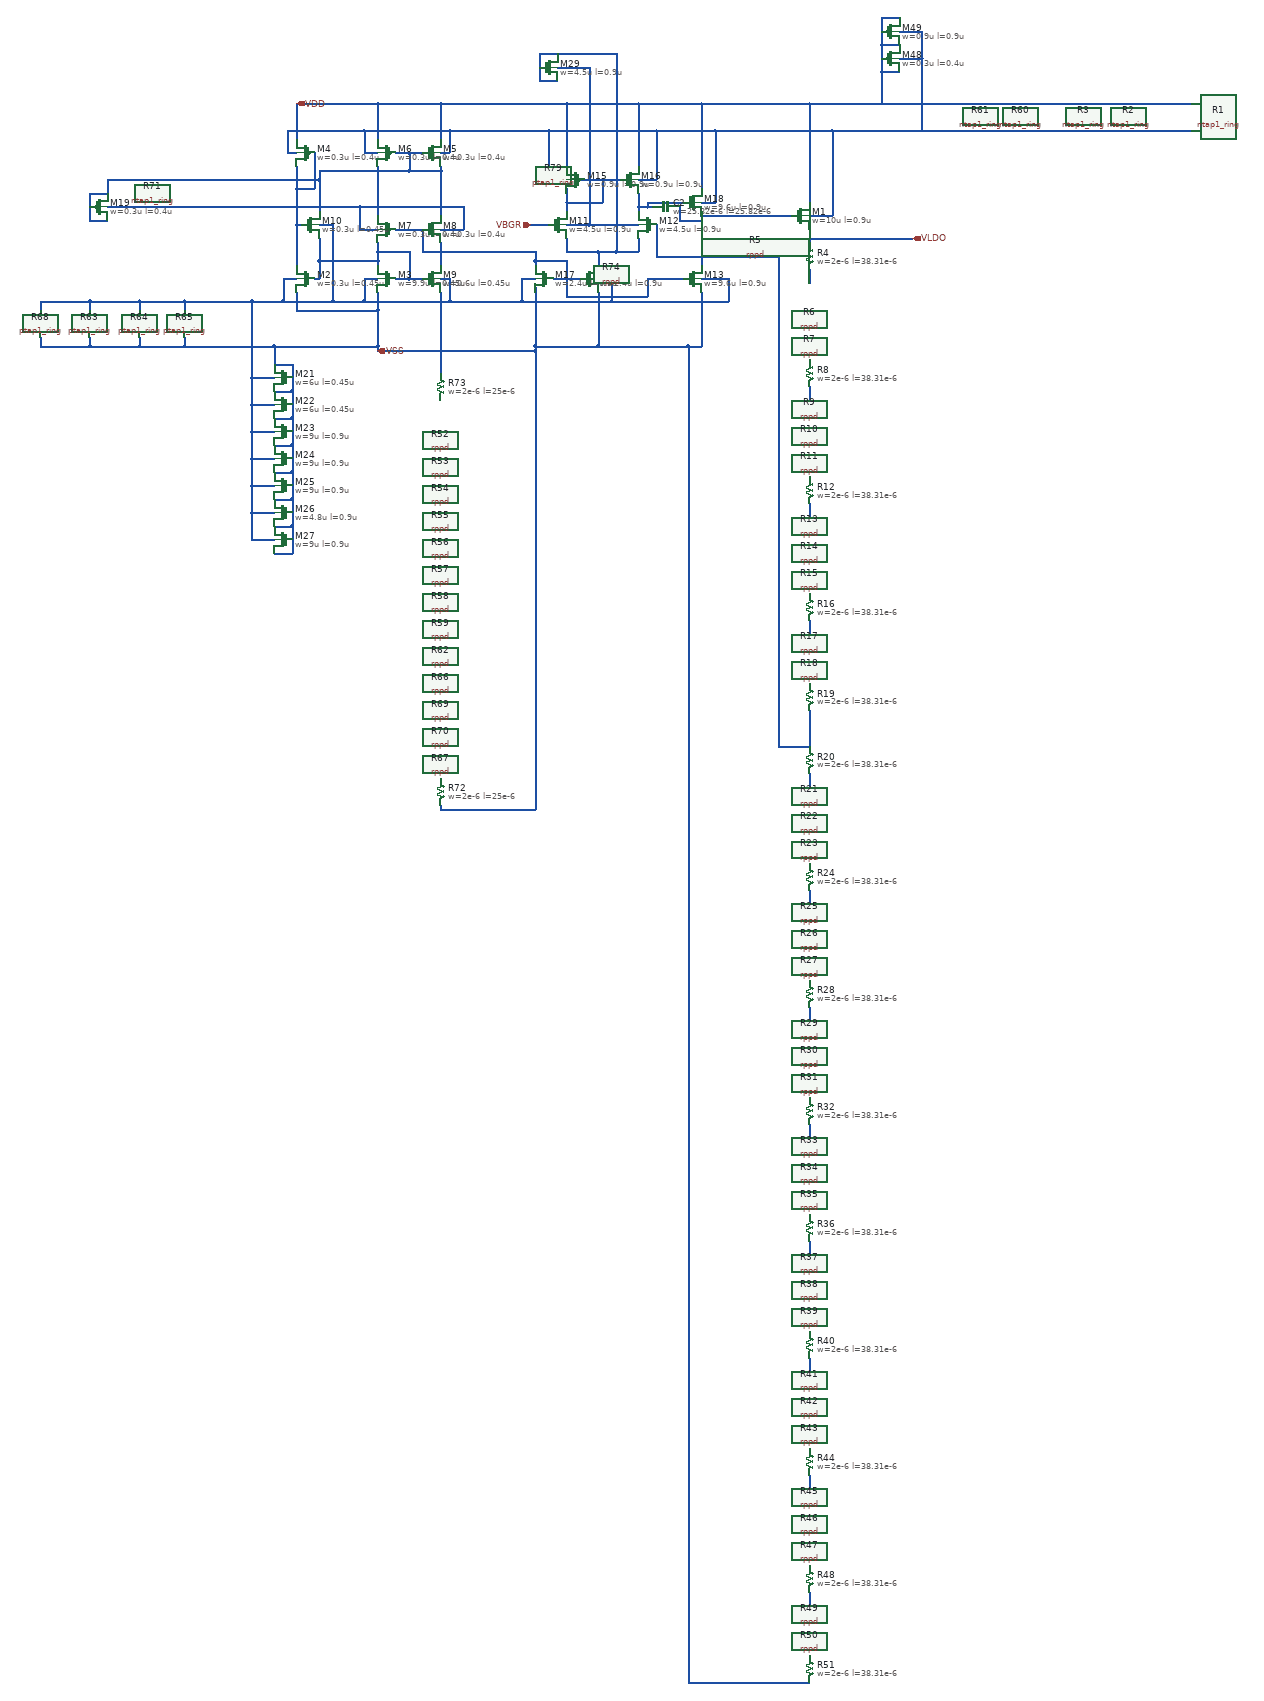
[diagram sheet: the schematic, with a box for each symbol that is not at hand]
v {xschem version=3.4.8RC file_version=1.3}
G {}
K {}
V {}
S {}
F {}
E {}
N -350 -1320 -240 -1320 {lab=VSS}
N -350 -1340 -350 -1320 {lab=VSS}
N -240 -1340 -240 -1320 {lab=VSS}
N -240 -1320 -130 -1320 {lab=VSS}
N -130 -1340 -130 -1320 {lab=VSS}
N -130 -1320 -30 -1320 {lab=VSS}
N -30 -1340 -30 -1320 {lab=VSS}
N 1520 -1860 2210 -1860 {lab=VDD}
N 210 -1160 210 -1100 {lab=VSS}
N 170 -1280 210 -1280 {lab=VSS}
N 170 -1220 210 -1220 {lab=VSS}
N 210 -1280 210 -1220 {lab=VSS}
N 170 -1320 170 -1280 {lab=VSS}
N 120 -1190 170 -1190 {lab=#net1}
N 120 -1250 120 -1190 {lab=#net1}
N 120 -1250 170 -1250 {lab=#net1}
N 170 -980 210 -980 {lab=VSS}
N 210 -1040 210 -980 {lab=VSS}
N 170 -1040 210 -1040 {lab=VSS}
N 210 -1100 210 -1040 {lab=VSS}
N 170 -920 210 -920 {lab=VSS}
N 210 -980 210 -920 {lab=VSS}
N 170 -1100 210 -1100 {lab=VSS}
N 170 -1160 210 -1160 {lab=VSS}
N 210 -1220 210 -1160 {lab=VSS}
N 120 -1130 170 -1130 {lab=#net1}
N 120 -1190 120 -1130 {lab=#net1}
N 120 -1070 170 -1070 {lab=#net1}
N 120 -1130 120 -1070 {lab=#net1}
N 120 -1010 170 -1010 {lab=#net1}
N 120 -1070 120 -1010 {lab=#net1}
N 120 -950 170 -950 {lab=#net1}
N 120 -1010 120 -950 {lab=#net1}
N 170 -860 210 -860 {lab=VSS}
N 210 -920 210 -860 {lab=VSS}
N 120 -890 170 -890 {lab=#net1}
N 120 -950 120 -890 {lab=#net1}
N 1360 -1610 1410 -1610 {lab=#net2}
N 470 -1750 500 -1750 {lab=#net3}
N 440 -1580 500 -1580 {lab=#net4}
N 400 -1510 400 -1500 {lab=#net5}
N 470 -1530 470 -1470 {lab=#net5}
N 400 -1530 470 -1530 {lab=#net5}
N 400 -1550 400 -1530 {lab=#net5}
N 400 -1440 400 -1400 {lab=VSS}
N 370 -1750 400 -1750 {lab=#net2}
N 400 -1720 400 -1610 {lab=#net6}
N 220 -1590 220 -1500 {lab=#net7}
N 270 -1510 270 -1470 {lab=#net5}
N 220 -1440 220 -1400 {lab=VSS}
N 270 -1590 300 -1590 {lab=#net1}
N 270 -1560 270 -1510 {lab=#net5}
N 220 -1590 230 -1590 {lab=#net7}
N 220 -1670 220 -1590 {lab=#net7}
N 260 -1750 260 -1670 {lab=#net7}
N 200 -1750 220 -1750 {lab=#net2}
N 540 -1750 560 -1750 {lab=#net2}
N 270 -1510 400 -1510 {lab=#net5}
N 400 -1530 400 -1510 {lab=#net5}
N 540 -1720 540 -1710 {lab=#net3}
N 540 -1530 540 -1500 {lab=#net4}
N 470 -1750 470 -1710 {lab=#net3}
N 440 -1750 470 -1750 {lab=#net3}
N 470 -1710 540 -1710 {lab=#net3}
N 270 -1690 270 -1620 {lab=#net3}
N 500 -1580 500 -1530 {lab=#net4}
N 500 -1530 540 -1530 {lab=#net4}
N 540 -1470 560 -1470 {lab=#net1}
N 470 -1470 500 -1470 {lab=#net5}
N 440 -1470 470 -1470 {lab=#net5}
N 220 -1670 260 -1670 {lab=#net7}
N 220 -1720 220 -1670 {lab=#net7}
N 260 -1470 270 -1470 {lab=#net5}
N 820 -1640 820 -1620 {lab=#net8}
N 820 -1560 820 -1530 {lab=#net9}
N 980 -1560 980 -1530 {lab=#net9}
N 750 -1510 750 -1500 {lab=#net4}
N 890 -1530 890 -1500 {lab=#net9}
N 820 -1470 860 -1470 {lab=#net4}
N 890 -1440 890 -1320 {lab=VSS}
N 750 -1450 750 -1320 {lab=VSS}
N 1000 -1470 1080 -1470 {lab=#net4}
N 1000 -1470 1000 -1430 {lab=#net4}
N 790 -1470 820 -1470 {lab=#net4}
N 820 -1430 1000 -1430 {lab=#net4}
N 820 -1470 820 -1430 {lab=#net4}
N 1120 -1470 1180 -1470 {lab=#net1}
N 980 -1630 980 -1620 {lab=#net10}
N 1120 -1640 1150 -1640 {lab=#net2}
N 780 -1690 820 -1690 {lab=#net2}
N 820 -1530 890 -1530 {lab=#net9}
N 890 -1470 920 -1470 {lab=#net1}
N 750 -1510 820 -1510 {lab=#net4}
N 820 -1510 820 -1470 {lab=#net4}
N 720 -1470 750 -1470 {lab=#net1}
N 900 -1690 940 -1690 {lab=#net8}
N 900 -1690 900 -1640 {lab=#net8}
N 850 -1690 900 -1690 {lab=#net8}
N 820 -1640 900 -1640 {lab=#net8}
N 820 -1670 820 -1640 {lab=#net8}
N 980 -1690 1020 -1690 {lab=#net2}
N 1000 -1630 1010 -1630 {lab=#net10}
N 1000 -1640 1080 -1640 {lab=#net10}
N 1000 -1640 1000 -1630 {lab=#net10}
N 980 -1630 1000 -1630 {lab=#net10}
N 980 -1660 980 -1630 {lab=#net10}
N 1070 -1630 1070 -1600 {lab=#net11}
N 1070 -1600 1120 -1600 {lab=#net11}
N 1120 -1610 1120 -1600 {lab=#net11}
N 1090 -1320 1120 -1320 {lab=VSS}
N 540 -1710 540 -1610 {lab=#net3}
N 1120 -1440 1120 -1320 {lab=VSS}
N 540 -1530 750 -1530 {lab=#net4}
N 750 -1530 750 -1510 {lab=#net4}
N 1120 -1600 1120 -1500 {lab=#net11}
N 1120 -1610 1320 -1610 {lab=#net11}
N 1120 -1620 1120 -1610 {lab=#net11}
N 400 -1400 400 -1320 {lab=VSS}
N 220 -1400 400 -1400 {lab=VSS}
N 1360 -1490 1360 -1460 {lab=#net12}
N 1360 -1560 1360 -1540 {lab=VLDO}
N 1360 -1580 1360 -1560 {lab=VLDO}
N 1360 -1560 1590 -1560 {lab=VLDO}
N 750 -1320 890 -1320 {lab=VSS}
N 1360 -1230 1360 -1200 {lab=#net13}
N 1360 -970 1360 -940 {lab=#net14}
N 1360 -710 1360 -680 {lab=#net15}
N 1360 -370 1360 -340 {lab=#net16}
N 1360 -110 1360 -80 {lab=#net17}
N 1360 150 1360 180 {lab=#net18}
N 1360 410 1360 440 {lab=#net19}
N 1360 670 1360 700 {lab=#net20}
N 1360 930 1360 960 {lab=#net21}
N 1360 1190 1360 1220 {lab=#net22}
N 1360 1450 1360 1480 {lab=#net23}
N 1290 -1520 1290 -430 {lab=#net24}
N 1020 -1520 1290 -1520 {lab=#net24}
N 1020 -1590 1020 -1520 {lab=#net24}
N 1290 -430 1360 -430 {lab=#net24}
N 1090 1650 1360 1650 {lab=VSS}
N 750 -1310 750 -290 {lab=VSS}
N 540 -290 750 -290 {lab=VSS}
N 740 -1590 780 -1590 {lab=VBGR}
N 370 -1800 370 -1750 {lab=#net2}
N 1410 -1800 1610 -1800 {lab=#net2}
N 560 -1800 560 -1750 {lab=#net2}
N 370 -1800 560 -1800 {lab=#net2}
N 780 -1800 780 -1690 {lab=#net2}
N 560 -1800 780 -1800 {lab=#net2}
N 1020 -1800 1020 -1690 {lab=#net2}
N 780 -1800 1020 -1800 {lab=#net2}
N 1150 -1800 1150 -1640 {lab=#net2}
N 1410 -1800 1410 -1610 {lab=#net2}
N 1150 -1800 1410 -1800 {lab=#net2}
N 200 -1800 370 -1800 {lab=#net2}
N 200 -1800 200 -1750 {lab=#net2}
N 540 -1550 540 -1530 {lab=#net4}
N 540 -1580 590 -1580 {lab=#net25}
N 360 -1580 400 -1580 {lab=#net25}
N 270 -1710 470 -1710 {lab=#net3}
N 1610 -1800 2210 -1800 {lab=#net2}
N 1520 -1990 1560 -1990 {lab=VDD}
N 1520 -2050 1560 -2050 {lab=VDD}
N 1520 -1930 1560 -1930 {lab=VDD}
N 1520 -1930 1520 -1860 {lab=VDD}
N 1520 -2050 1520 -1990 {lab=VDD}
N 1520 -1990 1520 -1930 {lab=VDD}
N 1560 -1960 1610 -1960 {lab=#net2}
N 1560 -2020 1610 -2020 {lab=#net2}
N 1610 -2020 1610 -1960 {lab=#net2}
N 1610 -1960 1610 -1800 {lab=#net2}
N 1360 -510 1360 -430 {lab=#net24}
N 1360 -1860 1520 -1860 {lab=VDD}
N 980 -1860 980 -1720 {lab=VDD}
N 1120 -1860 1120 -1670 {lab=VDD}
N 1360 -1860 1360 -1630 {lab=VDD}
N 1120 -1860 1360 -1860 {lab=VDD}
N 820 -1860 980 -1860 {lab=VDD}
N 220 -1860 220 -1780 {lab=VDD}
N 400 -1860 400 -1780 {lab=VDD}
N 220 -1860 400 -1860 {lab=VDD}
N 540 -1860 540 -1780 {lab=VDD}
N 400 -1860 540 -1860 {lab=VDD}
N 820 -1860 820 -1720 {lab=VDD}
N 540 -1860 820 -1860 {lab=VDD}
N 170 -1320 400 -1320 {lab=VSS}
N -350 -1420 -350 -1400 {lab=#net1}
N 920 -1420 1180 -1420 {lab=#net1}
N -30 -1420 -30 -1400 {lab=#net1}
N -130 -1420 -30 -1420 {lab=#net1}
N -130 -1420 -130 -1400 {lab=#net1}
N -240 -1420 -130 -1420 {lab=#net1}
N -240 -1420 -240 -1400 {lab=#net1}
N -350 -1420 -240 -1420 {lab=#net1}
N 190 -1470 220 -1470 {lab=#net1}
N 190 -1470 190 -1420 {lab=#net1}
N 120 -1420 190 -1420 {lab=#net1}
N 370 -1470 400 -1470 {lab=#net1}
N 370 -1470 370 -1420 {lab=#net1}
N 300 -1420 370 -1420 {lab=#net1}
N 300 -1590 300 -1420 {lab=#net1}
N 190 -1420 300 -1420 {lab=#net1}
N 560 -1470 560 -1420 {lab=#net1}
N 370 -1420 560 -1420 {lab=#net1}
N 720 -1470 720 -1420 {lab=#net1}
N 560 -1420 720 -1420 {lab=#net1}
N 1180 -1470 1180 -1420 {lab=#net1}
N 920 -1470 920 -1420 {lab=#net1}
N 720 -1420 920 -1420 {lab=#net1}
N -30 -1320 170 -1320 {lab=VSS}
N 120 -1420 120 -1250 {lab=#net1}
N -30 -1420 120 -1420 {lab=#net1}
N 590 -1630 590 -1580 {lab=#net25}
N 360 -1630 360 -1580 {lab=#net25}
N 360 -1630 590 -1630 {lab=#net25}
N -200 -1630 360 -1630 {lab=#net25}
N -240 -1600 -200 -1600 {lab=#net3}
N -240 -1660 -240 -1600 {lab=#net3}
N -240 -1660 -200 -1660 {lab=#net3}
N -200 -1690 -200 -1660 {lab=#net3}
N -200 -1690 270 -1690 {lab=#net3}
N 270 -1710 270 -1690 {lab=#net3}
N 1090 -1320 1090 1650 {lab=VSS}
N 890 -1320 1090 -1320 {lab=VSS}
N 760 -1910 800 -1910 {lab=#net9}
N 760 -1970 760 -1910 {lab=#net9}
N 870 -1590 980 -1590 {lab=#net26}
N 930 -1530 980 -1530 {lab=#net9}
N 890 -1530 930 -1530 {lab=#net9}
N 870 -1940 870 -1590 {lab=#net26}
N 820 -1590 870 -1590 {lab=#net26}
N 800 -1940 870 -1940 {lab=#net26}
N 930 -1970 930 -1530 {lab=#net9}
N 760 -1970 930 -1970 {lab=#net9}
N 400 -1320 400 -1310 {lab=VSS}
N 400 -1310 750 -1310 {lab=VSS}
N 750 -1320 750 -1310 {lab=VSS}
N 1020 -1800 1150 -1800 {lab=#net2}
N 980 -1860 1120 -1860 {lab=VDD}
N 540 -300 540 -290 {lab=VSS}
N 540 -1440 540 -1260 {lab=#net27}
C {ipin.sym} 740 -1590 0 0 {name=p5 lab=VBGR}
C {sg13g2_pr/ntap1_ring.sym} 2210 -1830 0 0 {name=R1
model=ntap1
spiceprefix=X
w=9.2e-6
l=2.8e-6
rw=0.3e-6
}
C {sg13g2_pr/ntap1_ring.sym} 2070 -1830 0 0 {name=R2
model=ntap1
spiceprefix=X
w=3.5e-6
l=2.8e-6
rw=0.3e-6
}
C {sg13g2_pr/ntap1_ring.sym} 1970 -1830 0 0 {name=R3
model=ntap1
spiceprefix=X
w=11.5e-6
l=3e-6
rw=0.3e-6
}
C {sg13g2_pr/ntap1_ring.sym} 1830 -1830 0 0 {name=R60
model=ntap1
spiceprefix=X
w=9.1e-6
l=12e-6
rw=0.3e-6
}
C {sg13g2_pr/ntap1_ring.sym} 1740 -1830 0 0 {name=R61
model=ntap1
spiceprefix=X
w=12.45e-6
l=7.8e-6
rw=0.3e-6
}
C {sg13g2_pr/ptap1_ring.sym} -240 -1370 2 1 {name=R63
model=ptap1
spiceprefix=X
w=2.5e-6
l=2.85e-6
rw=0.3e-6
}
C {sg13g2_pr/ptap1_ring.sym} -130 -1370 2 1 {name=R64
model=ptap1
spiceprefix=X
w=2.64e-6
l=2.84e-6
rw=0.3e-6
}
C {sg13g2_pr/ptap1_ring.sym} -30 -1370 2 1 {name=R65
model=ptap1
spiceprefix=X
w=19.5e-6
l=15.05e-6
rw=0.3e-6
}
C {sg13g2_pr/ptap1_ring.sym} -350 -1370 2 1 {name=R68
model=ptap1
spiceprefix=X
w=16.5e-6
l=6.9e-6
rw=0.3e-6
}
C {sg13g2_pr/ptap1_ring.sym} 900 -1940 1 1 {name=R79
model=ptap1
spiceprefix=X
w=10.7e-6
l=4.55e-6
rw=0.3e-6
}
C {sg13g2_pr/sg13_hv_nmos.sym} 190 -1250 0 1 {name=M21
l=0.45u
w=6u
ng=1
m=1
model=sg13_hv_nmos
spiceprefix=X
}
C {sg13g2_pr/sg13_hv_nmos.sym} 190 -1190 0 1 {name=M22
l=0.45u
w=6u
ng=1
m=1
model=sg13_hv_nmos
spiceprefix=X
}
C {sg13g2_pr/sg13_hv_nmos.sym} 190 -1130 0 1 {name=M23
l=0.9u
w=9u
ng=1
m=1
model=sg13_hv_nmos
spiceprefix=X
}
C {sg13g2_pr/sg13_hv_nmos.sym} 190 -1070 0 1 {name=M24
l=0.9u
w=9u
ng=1
m=1
model=sg13_hv_nmos
spiceprefix=X
}
C {sg13g2_pr/sg13_hv_nmos.sym} 190 -1010 0 1 {name=M25
l=0.9u
w=9u
ng=1
m=1
model=sg13_hv_nmos
spiceprefix=X
}
C {sg13g2_pr/sg13_hv_nmos.sym} 190 -950 0 1 {name=M26
l=0.9u
w=4.8u
ng=2
m=1
model=sg13_hv_nmos
spiceprefix=X
}
C {sg13g2_pr/sg13_hv_nmos.sym} 190 -890 0 1 {name=M27
l=0.9u
w=9u
ng=1
m=1
model=sg13_hv_nmos
spiceprefix=X
}
C {sg13g2_pr/sg13_hv_nmos.sym} 780 -1940 0 0 {name=M29
l=0.9u
w=4.5u
ng=1
m=1
model=sg13_hv_nmos
spiceprefix=X
}
C {sg13g2_pr/sg13_hv_pmos.sym} 1340 -1610 0 0 {name=M1
l=0.9u
w=10u
ng=1
m=4
model=sg13_hv_pmos
spiceprefix=X
}
C {sg13g2_pr/sg13_hv_nmos.sym} 240 -1470 0 1 {name=M2
l=0.45u
w=0.3u
ng=1
m=1
model=sg13_hv_nmos
spiceprefix=X
}
C {sg13g2_pr/sg13_hv_nmos.sym} 420 -1470 0 1 {name=M3
l=0.45u
w=9.9u
ng=1
m=1
model=sg13_hv_nmos
spiceprefix=X
}
C {sg13g2_pr/sg13_hv_pmos.sym} 240 -1750 0 1 {name=M4
l=0.4u
w=0.3u
ng=1
m=1
model=sg13_hv_pmos
spiceprefix=X
}
C {sg13g2_pr/sg13_hv_pmos.sym} 520 -1750 0 0 {name=M5
l=0.4u
w=0.3u
ng=1
m=1
model=sg13_hv_pmos
spiceprefix=X
}
C {sg13g2_pr/sg13_hv_pmos.sym} 420 -1750 0 1 {name=M6
l=0.4u
w=0.3u
ng=1
m=1
model=sg13_hv_pmos
spiceprefix=X
}
C {sg13g2_pr/sg13_hv_pmos.sym} 420 -1580 0 1 {name=M7
l=0.4u
w=0.3u
ng=1
m=1
model=sg13_hv_pmos
spiceprefix=X
}
C {sg13g2_pr/sg13_hv_pmos.sym} 520 -1580 0 0 {name=M8
l=0.4u
w=0.3u
ng=1
m=1
model=sg13_hv_pmos
spiceprefix=X
}
C {sg13g2_pr/sg13_hv_nmos.sym} 520 -1470 0 0 {name=M9
l=0.45u
w=0.6u
ng=1
m=1
model=sg13_hv_nmos
spiceprefix=X
}
C {sg13g2_pr/sg13_hv_nmos.sym} 250 -1590 0 0 {name=M10
l=0.45u
w=0.3u
ng=1
m=1
model=sg13_hv_nmos
spiceprefix=X
}
C {sg13g2_pr/sg13_hv_nmos.sym} 800 -1590 0 0 {name=M11
l=0.9u
w=4.5u
ng=1
m=1
model=sg13_hv_nmos
spiceprefix=X
}
C {sg13g2_pr/sg13_hv_nmos.sym} 1000 -1590 0 1 {name=M12
l=0.9u
w=4.5u
ng=1
m=1
model=sg13_hv_nmos
spiceprefix=X
}
C {sg13g2_pr/sg13_hv_nmos.sym} 1100 -1470 0 0 {name=M13
l=0.9u
w=9.6u
ng=8
m=4
model=sg13_hv_nmos
spiceprefix=X
}
C {sg13g2_pr/sg13_hv_nmos.sym} 870 -1470 0 0 {name=M14
l=0.9u
w=2.4u
ng=2
m=1
model=sg13_hv_nmos
spiceprefix=X
}
C {sg13g2_pr/sg13_hv_pmos.sym} 840 -1690 0 1 {name=M15
l=0.9u
w=0.9u
ng=1
m=1
model=sg13_hv_pmos
spiceprefix=X
}
C {sg13g2_pr/sg13_hv_pmos.sym} 960 -1690 0 0 {name=M16
l=0.9u
w=0.9u
ng=1
m=1
model=sg13_hv_pmos
spiceprefix=X
}
C {sg13g2_pr/sg13_hv_nmos.sym} 770 -1470 0 1 {name=M17
l=0.9u
w=2.4u
ng=2
m=1
model=sg13_hv_nmos
spiceprefix=X
}
C {sg13g2_pr/sg13_hv_pmos.sym} 1100 -1640 0 0 {name=M18
l=0.9u
w=9.6u
ng=1
m=5
model=sg13_hv_pmos
spiceprefix=X
}
C {sg13g2_pr/cap_cmim.sym} 1040 -1630 3 0 {name=C2
model=cap_cmim
w=25.82e-6
l=25.82e-6
m=1
spiceprefix=X}
C {sg13g2_pr/rppd.sym} 1360 -1520 0 0 {name=R4
w=2e-6
l=38.31e-6
model=rppd
body=0
spiceprefix=X
b=0
m=1
}
C {sg13g2_pr/rppd.sym} 1360 -1440 0 0 {name=R5
w=2e-6
l=38.31e-6
model=rppd
body=0
spiceprefix=X
b=0
m=1
}
C {sg13g2_pr/rppd.sym} 1360 -1380 0 0 {name=R6
w=2e-6
l=38.31e-6
model=rppd
body=0
spiceprefix=X
b=0
m=1
}
C {sg13g2_pr/rppd.sym} 1360 -1320 0 0 {name=R7
w=2e-6
l=38.31e-6
model=rppd
body=0
spiceprefix=X
b=0
m=1
}
C {sg13g2_pr/rppd.sym} 1360 -1260 0 0 {name=R8
w=2e-6
l=38.31e-6
model=rppd
body=0
spiceprefix=X
b=0
m=1
}
C {sg13g2_pr/rppd.sym} 1360 -1180 0 0 {name=R9
w=2e-6
l=38.31e-6
model=rppd
body=0
spiceprefix=X
b=0
m=1
}
C {sg13g2_pr/rppd.sym} 1360 -1120 0 0 {name=R10
w=2e-6
l=38.31e-6
model=rppd
body=0
spiceprefix=X
b=0
m=1
}
C {sg13g2_pr/rppd.sym} 1360 -1060 0 0 {name=R11
w=2e-6
l=38.31e-6
model=rppd
body=0
spiceprefix=X
b=0
m=1
}
C {sg13g2_pr/rppd.sym} 1360 -1000 0 0 {name=R12
w=2e-6
l=38.31e-6
model=rppd
body=0
spiceprefix=X
b=0
m=1
}
C {sg13g2_pr/rppd.sym} 1360 -920 0 0 {name=R13
w=2e-6
l=38.31e-6
model=rppd
body=0
spiceprefix=X
b=0
m=1
}
C {sg13g2_pr/rppd.sym} 1360 -860 0 0 {name=R14
w=2e-6
l=38.31e-6
model=rppd
body=0
spiceprefix=X
b=0
m=1
}
C {sg13g2_pr/rppd.sym} 1360 -800 0 0 {name=R15
w=2e-6
l=38.31e-6
model=rppd
body=0
spiceprefix=X
b=0
m=1
}
C {sg13g2_pr/rppd.sym} 1360 -740 0 0 {name=R16
w=2e-6
l=38.31e-6
model=rppd
body=0
spiceprefix=X
b=0
m=1
}
C {sg13g2_pr/rppd.sym} 1360 -660 0 0 {name=R17
w=2e-6
l=38.31e-6
model=rppd
body=0
spiceprefix=X
b=0
m=1
}
C {sg13g2_pr/rppd.sym} 1360 -600 0 0 {name=R18
w=2e-6
l=38.31e-6
model=rppd
body=0
spiceprefix=X
b=0
m=1
}
C {sg13g2_pr/rppd.sym} 1360 -540 0 0 {name=R19
w=2e-6
l=38.31e-6
model=rppd
body=0
spiceprefix=X
b=0
m=1
}
C {sg13g2_pr/rppd.sym} 1360 -400 0 0 {name=R20
w=2e-6
l=38.31e-6
model=rppd
body=0
spiceprefix=X
b=0
m=1
}
C {sg13g2_pr/rppd.sym} 1360 -320 0 0 {name=R21
w=2e-6
l=38.31e-6
model=rppd
body=0
spiceprefix=X
b=0
m=1
}
C {sg13g2_pr/rppd.sym} 1360 -260 0 0 {name=R22
w=2e-6
l=38.31e-6
model=rppd
body=0
spiceprefix=X
b=0
m=1
}
C {sg13g2_pr/rppd.sym} 1360 -200 0 0 {name=R23
w=2e-6
l=38.31e-6
model=rppd
body=0
spiceprefix=X
b=0
m=1
}
C {sg13g2_pr/rppd.sym} 1360 -140 0 0 {name=R24
w=2e-6
l=38.31e-6
model=rppd
body=0
spiceprefix=X
b=0
m=1
}
C {sg13g2_pr/rppd.sym} 1360 -60 0 0 {name=R25
w=2e-6
l=38.31e-6
model=rppd
body=0
spiceprefix=X
b=0
m=1
}
C {sg13g2_pr/rppd.sym} 1360 0 0 0 {name=R26
w=2e-6
l=38.31e-6
model=rppd
body=0
spiceprefix=X
b=0
m=1
}
C {sg13g2_pr/rppd.sym} 1360 60 0 0 {name=R27
w=2e-6
l=38.31e-6
model=rppd
body=0
spiceprefix=X
b=0
m=1
}
C {sg13g2_pr/rppd.sym} 1360 120 0 0 {name=R28
w=2e-6
l=38.31e-6
model=rppd
body=0
spiceprefix=X
b=0
m=1
}
C {sg13g2_pr/rppd.sym} 1360 200 0 0 {name=R29
w=2e-6
l=38.31e-6
model=rppd
body=0
spiceprefix=X
b=0
m=1
}
C {sg13g2_pr/rppd.sym} 1360 260 0 0 {name=R30
w=2e-6
l=38.31e-6
model=rppd
body=0
spiceprefix=X
b=0
m=1
}
C {sg13g2_pr/rppd.sym} 1360 320 0 0 {name=R31
w=2e-6
l=38.31e-6
model=rppd
body=0
spiceprefix=X
b=0
m=1
}
C {sg13g2_pr/rppd.sym} 1360 380 0 0 {name=R32
w=2e-6
l=38.31e-6
model=rppd
body=0
spiceprefix=X
b=0
m=1
}
C {sg13g2_pr/rppd.sym} 1360 460 0 0 {name=R33
w=2e-6
l=38.31e-6
model=rppd
body=0
spiceprefix=X
b=0
m=1
}
C {sg13g2_pr/rppd.sym} 1360 520 0 0 {name=R34
w=2e-6
l=38.31e-6
model=rppd
body=0
spiceprefix=X
b=0
m=1
}
C {sg13g2_pr/rppd.sym} 1360 580 0 0 {name=R35
w=2e-6
l=38.31e-6
model=rppd
body=0
spiceprefix=X
b=0
m=1
}
C {sg13g2_pr/rppd.sym} 1360 640 0 0 {name=R36
w=2e-6
l=38.31e-6
model=rppd
body=0
spiceprefix=X
b=0
m=1
}
C {sg13g2_pr/rppd.sym} 1360 720 0 0 {name=R37
w=2e-6
l=38.31e-6
model=rppd
body=0
spiceprefix=X
b=0
m=1
}
C {sg13g2_pr/rppd.sym} 1360 780 0 0 {name=R38
w=2e-6
l=38.31e-6
model=rppd
body=0
spiceprefix=X
b=0
m=1
}
C {sg13g2_pr/rppd.sym} 1360 840 0 0 {name=R39
w=2e-6
l=38.31e-6
model=rppd
body=0
spiceprefix=X
b=0
m=1
}
C {sg13g2_pr/rppd.sym} 1360 900 0 0 {name=R40
w=2e-6
l=38.31e-6
model=rppd
body=0
spiceprefix=X
b=0
m=1
}
C {sg13g2_pr/rppd.sym} 1360 980 0 0 {name=R41
w=2e-6
l=38.31e-6
model=rppd
body=0
spiceprefix=X
b=0
m=1
}
C {sg13g2_pr/rppd.sym} 1360 1040 0 0 {name=R42
w=2e-6
l=38.31e-6
model=rppd
body=0
spiceprefix=X
b=0
m=1
}
C {sg13g2_pr/rppd.sym} 1360 1100 0 0 {name=R43
w=2e-6
l=38.31e-6
model=rppd
body=0
spiceprefix=X
b=0
m=1
}
C {sg13g2_pr/rppd.sym} 1360 1160 0 0 {name=R44
w=2e-6
l=38.31e-6
model=rppd
body=0
spiceprefix=X
b=0
m=1
}
C {sg13g2_pr/rppd.sym} 1360 1240 0 0 {name=R45
w=2e-6
l=38.31e-6
model=rppd
body=0
spiceprefix=X
b=0
m=1
}
C {sg13g2_pr/rppd.sym} 1360 1300 0 0 {name=R46
w=2e-6
l=38.31e-6
model=rppd
body=0
spiceprefix=X
b=0
m=1
}
C {sg13g2_pr/rppd.sym} 1360 1360 0 0 {name=R47
w=2e-6
l=38.31e-6
model=rppd
body=0
spiceprefix=X
b=0
m=1
}
C {sg13g2_pr/rppd.sym} 1360 1420 0 0 {name=R48
w=2e-6
l=38.31e-6
model=rppd
body=0
spiceprefix=X
b=0
m=1
}
C {sg13g2_pr/rppd.sym} 1360 1500 0 0 {name=R49
w=2e-6
l=38.31e-6
model=rppd
body=0
spiceprefix=X
b=0
m=1
}
C {sg13g2_pr/rppd.sym} 1360 1560 0 0 {name=R50
w=2e-6
l=38.31e-6
model=rppd
body=0
spiceprefix=X
b=0
m=1
}
C {sg13g2_pr/rppd.sym} 1360 1620 0 0 {name=R51
w=2e-6
l=38.31e-6
model=rppd
body=0
spiceprefix=X
b=0
m=1
}
C {opin.sym} 1590 -1560 0 0 {name=p8 lab=VLDO}
C {sg13g2_pr/sg13_hv_pmos.sym} 1540 -1960 0 0 {name=M48
l=0.4u
w=0.3u
ng=1
m=1
model=sg13_hv_pmos
spiceprefix=X
}
C {sg13g2_pr/sg13_hv_pmos.sym} 1540 -2020 0 0 {name=M49
l=0.9u
w=0.9u
ng=1
m=1
model=sg13_hv_pmos
spiceprefix=X
}
C {sg13g2_pr/ntap1_ring.sym} -100 -1660 0 0 {name=R71
model=ntap1
spiceprefix=X
w=2.7e-6
l=8.8e-6
rw=0.3e-6
}
C {sg13g2_pr/sg13_hv_pmos.sym} -220 -1630 0 0 {name=M19
l=0.4u
w=0.3u
ng=1
m=1
model=sg13_hv_pmos
spiceprefix=X
}
C {iopin.sym} 220 -1860 0 1 {name=p1 lab=VDD}
C {iopin.sym} 400 -1310 0 1 {name=p2 lab=VSS}
C {sg13g2_pr/rppd.sym} 540 -1110 0 0 {name=R52
w=2e-6
l=25e-6
model=rppd
body=0
spiceprefix=X
b=0
m=1
}
C {sg13g2_pr/rppd.sym} 540 -1050 0 0 {name=R53
w=2e-6
l=25e-6
model=rppd
body=0
spiceprefix=X
b=0
m=1
}
C {sg13g2_pr/rppd.sym} 540 -990 0 0 {name=R54
w=2e-6
l=25e-6
model=rppd
body=0
spiceprefix=X
b=0
m=1
}
C {sg13g2_pr/rppd.sym} 540 -930 0 0 {name=R55
w=2e-6
l=25e-6
model=rppd
body=0
spiceprefix=X
b=0
m=1
}
C {sg13g2_pr/rppd.sym} 540 -870 0 0 {name=R56
w=2e-6
l=25e-6
model=rppd
body=0
spiceprefix=X
b=0
m=1
}
C {sg13g2_pr/rppd.sym} 540 -810 0 0 {name=R57
w=2e-6
l=25e-6
model=rppd
body=0
spiceprefix=X
b=0
m=1
}
C {sg13g2_pr/rppd.sym} 540 -750 0 0 {name=R58
w=2e-6
l=25e-6
model=rppd
body=0
spiceprefix=X
b=0
m=1
}
C {sg13g2_pr/rppd.sym} 540 -690 0 0 {name=R59
w=2e-6
l=25e-6
model=rppd
body=0
spiceprefix=X
b=0
m=1
}
C {sg13g2_pr/rppd.sym} 540 -630 0 0 {name=R62
w=2e-6
l=25e-6
model=rppd
body=0
spiceprefix=X
b=0
m=1
}
C {sg13g2_pr/rppd.sym} 540 -570 0 0 {name=R66
w=2e-6
l=25e-6
model=rppd
body=0
spiceprefix=X
b=0
m=1
}
C {sg13g2_pr/rppd.sym} 540 -510 0 0 {name=R69
w=2e-6
l=25e-6
model=rppd
body=0
spiceprefix=X
b=0
m=1
}
C {sg13g2_pr/rppd.sym} 540 -450 0 0 {name=R70
w=2e-6
l=25e-6
model=rppd
body=0
spiceprefix=X
b=0
m=1
}
C {sg13g2_pr/rppd.sym} 540 -390 0 0 {name=R67
w=2e-6
l=25e-6
model=rppd
body=0
spiceprefix=X
b=0
m=1
}
C {sg13g2_pr/rppd.sym} 540 -330 0 0 {name=R72
w=2e-6
l=25e-6
model=rppd
body=0
spiceprefix=X
b=0
m=1
}
C {sg13g2_pr/rppd.sym} 540 -1230 0 0 {name=R73
w=2e-6
l=25e-6
model=rppd
body=0
spiceprefix=X
b=0
m=1
}
C {sg13g2_pr/rppd.sym} 540 -1170 0 0 {name=R74
w=2e-6
l=25e-6
model=rppd
body=0
spiceprefix=X
b=0
m=1
}
